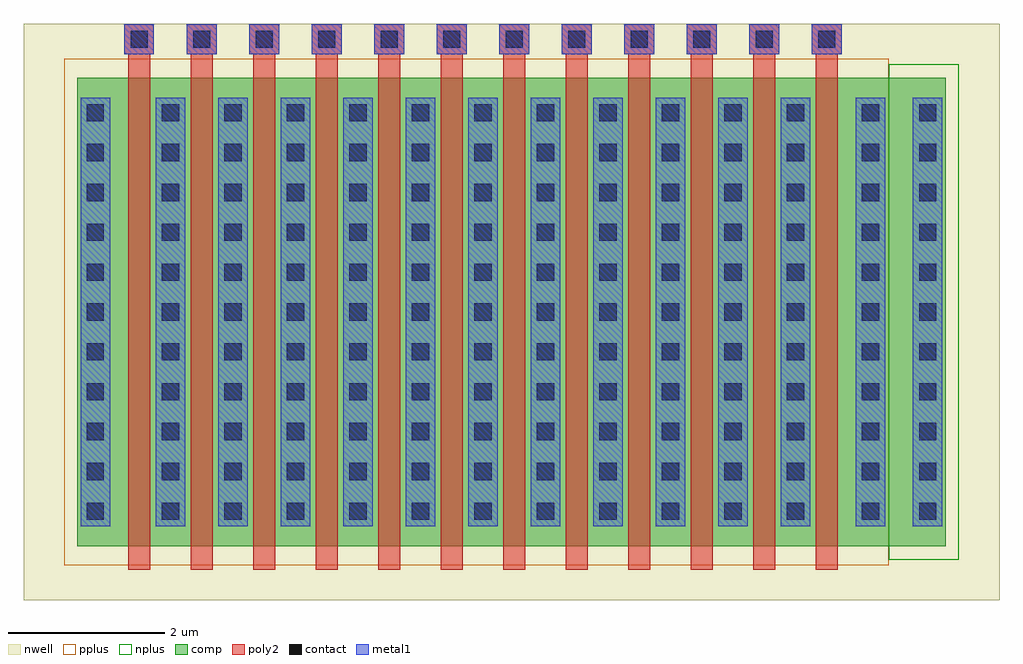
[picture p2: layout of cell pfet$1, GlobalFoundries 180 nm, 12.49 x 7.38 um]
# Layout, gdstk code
import gdstk
lib = gdstk.Library(unit=1e-6, precision=1e-09)
def R(c, l, rs):  # rectangles x0, y0, x1, y1
    for r in rs: c.add(gdstk.rectangle(r[:2], r[2:], *l))
def A(c, l, x, y, w, h, nx, ny, dx, dy):  # array of equal rectangles
    R(c, l, [(x+i*dx, y+j*dy, x+i*dx+w, y+j*dy+h) for i in range(nx) for j in range(ny)])
nwell = (21, 0)
comp = (22, 0)
poly2 = (30, 0)
pplus = (31, 0)
nplus = (32, 0)
contact = (33, 0)
metal1 = (34, 0)

pfet_1 = lib.new_cell('pfet$1')
R(pfet_1, nwell, [(-1.15,-0.69,11.34,6.69)])
R(pfet_1, comp, [(-0.46,0,0,6), (0,0,9.46,6), (9.46,0,9.92,6), (9.92,0,10.65,6)])
A(pfet_1, poly2, 0.19, -0.3, 0.28, 6.6, 12, 1, 0.8, 0)
A(pfet_1, poly2, 0.14, 6.3, 0.38, 0.38, 12, 1, 0.8, 0)
R(pfet_1, pplus, [(-0.63,-0.24,9.92,6.24)])
R(pfet_1, nplus, [(9.92,-0.17,10.82,6.17)])
A(pfet_1, contact, -0.34, 0.34, 0.22, 0.22, 1, 11, 0, 0.51)
A(pfet_1, contact, 0.62, 0.34, 0.22, 0.22, 11, 11, 0.8, 0.51)
A(pfet_1, contact, 9.58, 0.34, 0.22, 0.22, 1, 11, 0, 0.51)
A(pfet_1, contact, 10.31, 0.34, 0.22, 0.22, 1, 11, 0, 0.51)
A(pfet_1, contact, 0.22, 6.38, 0.22, 0.22, 12, 1, 0.8, 0)
A(pfet_1, metal1, 0.54, 0.26, 0.38, 5.48, 11, 1, 0.8, 0)
A(pfet_1, metal1, 0.14, 6.299, 0.38, 0.382, 12, 1, 0.8, 0)
R(pfet_1, metal1, [(-0.42,0.26,-0.04,5.74), (9.5,0.26,9.88,5.74), (10.23,0.26,10.61,5.74)])

lib.write_gds('pfet_1.gds')
